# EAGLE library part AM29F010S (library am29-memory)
1-Megabit FLASH MEMORY (128 K x 8 bit) 5 V-only

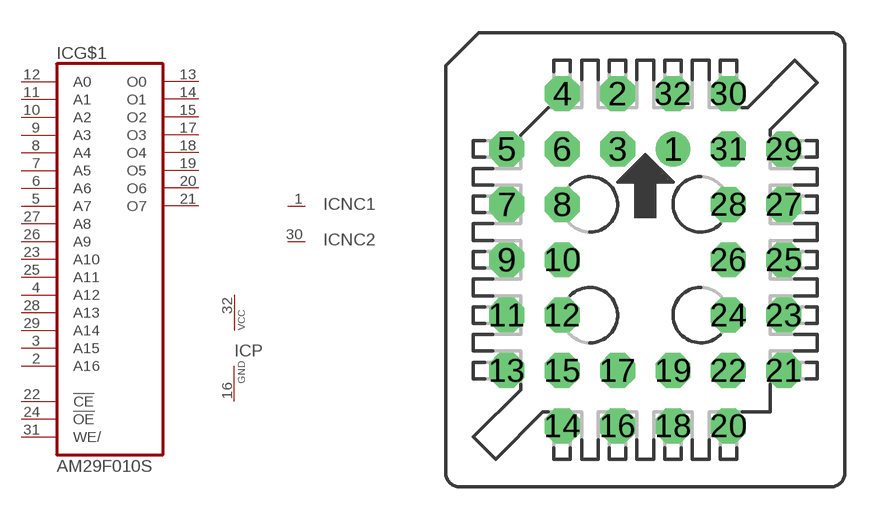
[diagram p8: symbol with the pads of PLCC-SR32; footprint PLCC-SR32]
Designator prefix IC; gates P=VCC-GND NC1=NC NC2=NC G$1=AM29F010

## AM29F010S  [PLCC-SR32]
1  NC1:NC  nc
2  G$1:A16  in
3  G$1:A15  in
4  G$1:A12  in
5  G$1:A7  in
6  G$1:A6  in
7  G$1:A5  in
8  G$1:A4  in
9  G$1:A3  in
10  G$1:A2  in
11  G$1:A1  in
12  G$1:A0  in
13  G$1:O0  hiz
14  G$1:O1  hiz
15  G$1:O2  hiz
16  P:GND  pwr
17  G$1:O3  hiz
18  G$1:O4  hiz
19  G$1:O5  hiz
20  G$1:O6  hiz
21  G$1:O7  hiz
22  G$1:!CE  in
23  G$1:A10  in
24  G$1:!OE  in
25  G$1:A11  in
26  G$1:A9  in
27  G$1:A8  in
28  G$1:A13  in
29  G$1:A14  in
30  NC2:NC  nc
31  G$1:WE/  in
32  P:VCC  pwr

## Footprint PLCC-SR32 (pad centres in mm)
PLCC32 Socket
drill 0.7 pad 1.6 round: 1 1.27,5.08
drill 0.7 pad 1.6 octagon: 2 -1.27,7.62; 3 -1.27,5.08; 4 -3.81,7.62; 5 -6.35,5.08; 6 -3.81,5.08; 7 -6.35,2.54; 8 -3.81,2.54; 9 -6.35,0; 10 -3.81,0; 11 -6.35,-2.54; 12 -3.81,-2.54; 13 -6.35,-5.08; 14 -3.81,-7.62; 15 -3.81,-5.08; 16 -1.27,-7.62; 17 -1.27,-5.08; 18 1.27,-7.62; 19 1.27,-5.08; 20 3.81,-7.62; 21 6.35,-5.08; 22 3.81,-5.08; 23 6.35,-2.54; 24 3.81,-2.54; 25 6.35,0; 26 3.81,0; 27 6.35,2.54; 28 3.81,2.54; 29 6.35,5.08; 30 3.81,7.62; 31 3.81,5.08; 32 1.27,7.62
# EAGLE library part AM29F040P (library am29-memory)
4-Megabit FLASH MEMORY (512 K x 8 bit) 5 V-only

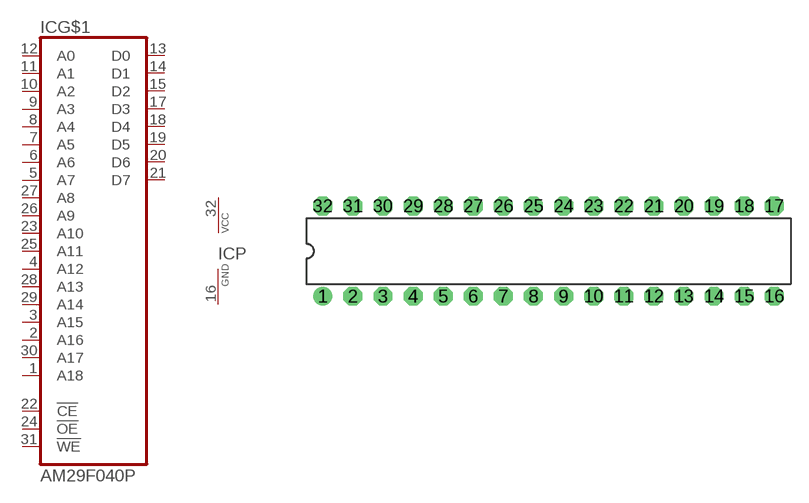
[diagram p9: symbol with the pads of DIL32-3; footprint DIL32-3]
Designator prefix IC; gates G$1=AM29F040 P=VCC-GND

## AM29F040P  [DIL32-3]
1  G$1:A18  in
2  G$1:A16  in
3  G$1:A15  in
4  G$1:A12  in
5  G$1:A7  in
6  G$1:A6  in
7  G$1:A5  in
8  G$1:A4  in
9  G$1:A3  in
10  G$1:A2  in
11  G$1:A1  in
12  G$1:A0  in
13  G$1:D0  hiz
14  G$1:D1  hiz
15  G$1:D2  hiz
16  P:GND  pwr
17  G$1:D3  hiz
18  G$1:D4  hiz
19  G$1:D5  hiz
20  G$1:D6  hiz
21  G$1:D7  hiz
22  G$1:!CE  in
23  G$1:A10  in
24  G$1:!OE  in
25  G$1:A11  in
26  G$1:A9  in
27  G$1:A8  in
28  G$1:A13  in
29  G$1:A14  in
30  G$1:A17  in
31  G$1:!WE  in
32  P:VCC  pwr

## Footprint DIL32-3 (pad centres in mm)
Dual In Line 0.3 inch
drill 0.813 pad 1.6 round: 1 -19.05,-3.81
drill 0.813 pad 1.6 octagon: 2 -16.51,-3.81; 3 -13.97,-3.81; 4 -11.43,-3.81; 5 -8.89,-3.81; 6 -6.35,-3.81; 7 -3.81,-3.81; 8 -1.27,-3.81; 9 1.27,-3.81; 10 3.81,-3.81; 11 6.35,-3.81; 12 8.89,-3.81; 13 11.43,-3.81; 14 13.97,-3.81; 15 16.51,-3.81; 16 19.05,-3.81; 17 19.05,3.81; 18 16.51,3.81; 19 13.97,3.81; 20 11.43,3.81; 21 8.89,3.81; 22 6.35,3.81; 23 3.81,3.81; 24 1.27,3.81; 25 -1.27,3.81; 26 -3.81,3.81; 27 -6.35,3.81; 28 -8.89,3.81; 29 -11.43,3.81; 30 -13.97,3.81; 31 -16.51,3.81; 32 -19.05,3.81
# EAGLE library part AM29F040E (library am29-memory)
4-Megabit FLASH MEMORY (512 K x 8 bit) 5 V-only

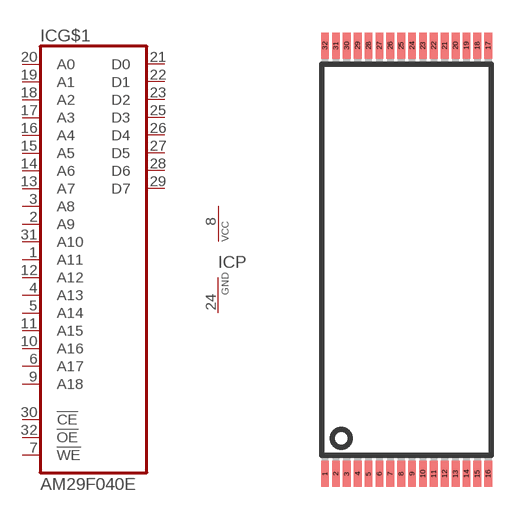
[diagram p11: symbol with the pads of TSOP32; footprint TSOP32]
Designator prefix IC; gates G$1=AM29F040 P=VCC-GND

## AM29F040E  [TSOP32]
1  G$1:A11  in
2  G$1:A9  in
3  G$1:A8  in
4  G$1:A13  in
5  G$1:A14  in
6  G$1:A17  in
7  G$1:!WE  in
8  P:VCC  pwr
9  G$1:A18  in
10  G$1:A16  in
11  G$1:A15  in
12  G$1:A12  in
13  G$1:A7  in
14  G$1:A6  in
15  G$1:A5  in
16  G$1:A4  in
17  G$1:A3  in
18  G$1:A2  in
19  G$1:A1  in
20  G$1:A0  in
21  G$1:D0  hiz
22  G$1:D1  hiz
23  G$1:D2  hiz
24  P:GND  pwr
25  G$1:D3  hiz
26  G$1:D4  hiz
27  G$1:D5  hiz
28  G$1:D6  hiz
29  G$1:D7  hiz
30  G$1:!CE  in
31  G$1:A10  in
32  G$1:!OE  in

## Footprint TSOP32 (pad centres in mm)
Thin Small Outline Plastic Package
smd 0.36 x 1.2: 1 -3.75,-9.85; 2 -3.25,-9.85; 3 -2.75,-9.85; 4 -2.25,-9.85; 5 -1.75,-9.85; 6 -1.25,-9.85; 7 -0.75,-9.85; 8 -0.25,-9.85; 9 0.25,-9.85; 10 0.75,-9.85; 11 1.25,-9.85; 12 1.75,-9.85; 13 2.25,-9.85; 14 2.75,-9.85; 15 3.25,-9.85; 16 3.75,-9.85; 17 3.75,9.85; 18 3.25,9.85; 19 2.75,9.85; 20 2.25,9.85; 21 1.75,9.85; 22 1.25,9.85; 23 0.75,9.85; 24 0.25,9.85; 25 -0.25,9.85; 26 -0.75,9.85; 27 -1.25,9.85; 28 -1.75,9.85; 29 -2.25,9.85; 30 -2.75,9.85; 31 -3.25,9.85; 32 -3.75,9.85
